VERSION 5.7 ;
BUSBITCHARS "[]" ;
DIVIDERCHAR "/" ;

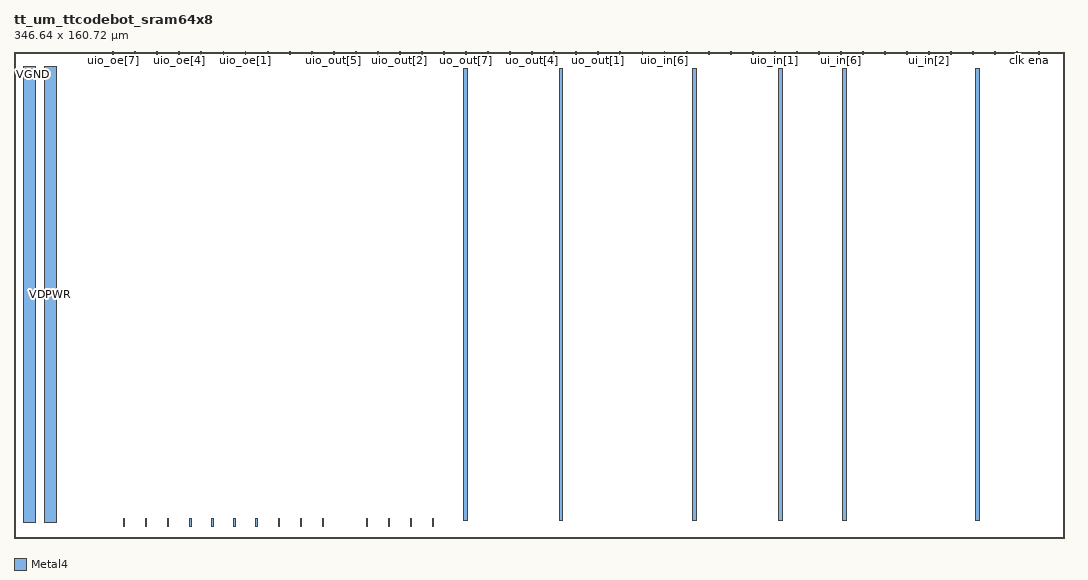
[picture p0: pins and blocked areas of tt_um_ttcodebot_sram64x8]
MACRO tt_um_ttcodebot_sram64x8
  CLASS BLOCK ;
  FOREIGN tt_um_ttcodebot_sram64x8 0 0 ;
  ORIGIN 0 0 ;
  SIZE 346.640 BY 160.720 ;
  PIN clk
    DIRECTION INPUT ;
    USE SIGNAL ;
    PORT
      LAYER Metal4 ;
        RECT 331.090 159.720 331.390 160.720 ;
    END
  END clk
  PIN ena
    DIRECTION INPUT ;
    USE SIGNAL ;
    PORT
      LAYER Metal4 ;
        RECT 338.370 159.720 338.670 160.720 ;
    END
  END ena
  PIN rst_n
    DIRECTION INPUT ;
    USE SIGNAL ;
    PORT
      LAYER Metal4 ;
        RECT 323.810 159.720 324.110 160.720 ;
    END
  END rst_n
  PIN ui_in[0]
    DIRECTION INPUT ;
    USE SIGNAL ;
    PORT
      LAYER Metal4 ;
        RECT 316.530 159.720 316.830 160.720 ;
    END
  END ui_in[0]
  PIN ui_in[1]
    DIRECTION INPUT ;
    USE SIGNAL ;
    PORT
      LAYER Metal4 ;
        RECT 309.250 159.720 309.550 160.720 ;
    END
  END ui_in[1]
  PIN ui_in[2]
    DIRECTION INPUT ;
    USE SIGNAL ;
    PORT
      LAYER Metal4 ;
        RECT 301.970 159.720 302.270 160.720 ;
    END
  END ui_in[2]
  PIN ui_in[3]
    DIRECTION INPUT ;
    USE SIGNAL ;
    PORT
      LAYER Metal4 ;
        RECT 294.690 159.720 294.990 160.720 ;
    END
  END ui_in[3]
  PIN ui_in[4]
    DIRECTION INPUT ;
    USE SIGNAL ;
    PORT
      LAYER Metal4 ;
        RECT 287.410 159.720 287.710 160.720 ;
    END
  END ui_in[4]
  PIN ui_in[5]
    DIRECTION INPUT ;
    USE SIGNAL ;
    PORT
      LAYER Metal4 ;
        RECT 280.130 159.720 280.430 160.720 ;
    END
  END ui_in[5]
  PIN ui_in[6]
    DIRECTION INPUT ;
    USE SIGNAL ;
    PORT
      LAYER Metal4 ;
        RECT 272.850 159.720 273.150 160.720 ;
    END
  END ui_in[6]
  PIN ui_in[7]
    DIRECTION INPUT ;
    USE SIGNAL ;
    PORT
      LAYER Metal4 ;
        RECT 265.570 159.720 265.870 160.720 ;
    END
  END ui_in[7]
  PIN uio_in[0]
    DIRECTION INPUT ;
    USE SIGNAL ;
    PORT
      LAYER Metal4 ;
        RECT 258.290 159.720 258.590 160.720 ;
    END
  END uio_in[0]
  PIN uio_in[1]
    DIRECTION INPUT ;
    USE SIGNAL ;
    PORT
      LAYER Metal4 ;
        RECT 251.010 159.720 251.310 160.720 ;
    END
  END uio_in[1]
  PIN uio_in[2]
    DIRECTION INPUT ;
    USE SIGNAL ;
    PORT
      LAYER Metal4 ;
        RECT 243.730 159.720 244.030 160.720 ;
    END
  END uio_in[2]
  PIN uio_in[3]
    DIRECTION INPUT ;
    USE SIGNAL ;
    PORT
      LAYER Metal4 ;
        RECT 236.450 159.720 236.750 160.720 ;
    END
  END uio_in[3]
  PIN uio_in[4]
    DIRECTION INPUT ;
    USE SIGNAL ;
    PORT
      LAYER Metal4 ;
        RECT 229.170 159.720 229.470 160.720 ;
    END
  END uio_in[4]
  PIN uio_in[5]
    DIRECTION INPUT ;
    USE SIGNAL ;
    PORT
      LAYER Metal4 ;
        RECT 221.890 159.720 222.190 160.720 ;
    END
  END uio_in[5]
  PIN uio_in[6]
    DIRECTION INPUT ;
    USE SIGNAL ;
    PORT
      LAYER Metal4 ;
        RECT 214.610 159.720 214.910 160.720 ;
    END
  END uio_in[6]
  PIN uio_in[7]
    DIRECTION INPUT ;
    USE SIGNAL ;
    PORT
      LAYER Metal4 ;
        RECT 207.330 159.720 207.630 160.720 ;
    END
  END uio_in[7]
  PIN uo_out[0]
    DIRECTION OUTPUT ;
    USE SIGNAL ;
    PORT
      LAYER Metal4 ;
        RECT 200.050 159.720 200.350 160.720 ;
    END
  END uo_out[0]
  PIN uo_out[1]
    DIRECTION OUTPUT ;
    USE SIGNAL ;
    PORT
      LAYER Metal4 ;
        RECT 192.770 159.720 193.070 160.720 ;
    END
  END uo_out[1]
  PIN uo_out[2]
    DIRECTION OUTPUT ;
    USE SIGNAL ;
    PORT
      LAYER Metal4 ;
        RECT 185.490 159.720 185.790 160.720 ;
    END
  END uo_out[2]
  PIN uo_out[3]
    DIRECTION OUTPUT ;
    USE SIGNAL ;
    PORT
      LAYER Metal4 ;
        RECT 178.210 159.720 178.510 160.720 ;
    END
  END uo_out[3]
  PIN uo_out[4]
    DIRECTION OUTPUT ;
    USE SIGNAL ;
    PORT
      LAYER Metal4 ;
        RECT 170.930 159.720 171.230 160.720 ;
    END
  END uo_out[4]
  PIN uo_out[5]
    DIRECTION OUTPUT ;
    USE SIGNAL ;
    PORT
      LAYER Metal4 ;
        RECT 163.650 159.720 163.950 160.720 ;
    END
  END uo_out[5]
  PIN uo_out[6]
    DIRECTION OUTPUT ;
    USE SIGNAL ;
    PORT
      LAYER Metal4 ;
        RECT 156.370 159.720 156.670 160.720 ;
    END
  END uo_out[6]
  PIN uo_out[7]
    DIRECTION OUTPUT ;
    USE SIGNAL ;
    PORT
      LAYER Metal4 ;
        RECT 149.090 159.720 149.390 160.720 ;
    END
  END uo_out[7]
  PIN uio_out[0]
    DIRECTION OUTPUT ;
    USE SIGNAL ;
    PORT
      LAYER Metal4 ;
        RECT 141.810 159.720 142.110 160.720 ;
    END
  END uio_out[0]
  PIN uio_out[1]
    DIRECTION OUTPUT ;
    USE SIGNAL ;
    PORT
      LAYER Metal4 ;
        RECT 134.530 159.720 134.830 160.720 ;
    END
  END uio_out[1]
  PIN uio_out[2]
    DIRECTION OUTPUT ;
    USE SIGNAL ;
    PORT
      LAYER Metal4 ;
        RECT 127.250 159.720 127.550 160.720 ;
    END
  END uio_out[2]
  PIN uio_out[3]
    DIRECTION OUTPUT ;
    USE SIGNAL ;
    PORT
      LAYER Metal4 ;
        RECT 119.970 159.720 120.270 160.720 ;
    END
  END uio_out[3]
  PIN uio_out[4]
    DIRECTION OUTPUT ;
    USE SIGNAL ;
    PORT
      LAYER Metal4 ;
        RECT 112.690 159.720 112.990 160.720 ;
    END
  END uio_out[4]
  PIN uio_out[5]
    DIRECTION OUTPUT ;
    USE SIGNAL ;
    PORT
      LAYER Metal4 ;
        RECT 105.410 159.720 105.710 160.720 ;
    END
  END uio_out[5]
  PIN uio_out[6]
    DIRECTION OUTPUT ;
    USE SIGNAL ;
    PORT
      LAYER Metal4 ;
        RECT 98.130 159.720 98.430 160.720 ;
    END
  END uio_out[6]
  PIN uio_out[7]
    DIRECTION OUTPUT ;
    USE SIGNAL ;
    PORT
      LAYER Metal4 ;
        RECT 90.850 159.720 91.150 160.720 ;
    END
  END uio_out[7]
  PIN uio_oe[0]
    DIRECTION OUTPUT ;
    USE SIGNAL ;
    PORT
      LAYER Metal4 ;
        RECT 83.570 159.720 83.870 160.720 ;
    END
  END uio_oe[0]
  PIN uio_oe[1]
    DIRECTION OUTPUT ;
    USE SIGNAL ;
    PORT
      LAYER Metal4 ;
        RECT 76.290 159.720 76.590 160.720 ;
    END
  END uio_oe[1]
  PIN uio_oe[2]
    DIRECTION OUTPUT ;
    USE SIGNAL ;
    PORT
      LAYER Metal4 ;
        RECT 69.010 159.720 69.310 160.720 ;
    END
  END uio_oe[2]
  PIN uio_oe[3]
    DIRECTION OUTPUT ;
    USE SIGNAL ;
    PORT
      LAYER Metal4 ;
        RECT 61.730 159.720 62.030 160.720 ;
    END
  END uio_oe[3]
  PIN uio_oe[4]
    DIRECTION OUTPUT ;
    USE SIGNAL ;
    PORT
      LAYER Metal4 ;
        RECT 54.450 159.720 54.750 160.720 ;
    END
  END uio_oe[4]
  PIN uio_oe[5]
    DIRECTION OUTPUT ;
    USE SIGNAL ;
    PORT
      LAYER Metal4 ;
        RECT 47.170 159.720 47.470 160.720 ;
    END
  END uio_oe[5]
  PIN uio_oe[6]
    DIRECTION OUTPUT ;
    USE SIGNAL ;
    PORT
      LAYER Metal4 ;
        RECT 39.890 159.720 40.190 160.720 ;
    END
  END uio_oe[6]
  PIN uio_oe[7]
    DIRECTION OUTPUT ;
    USE SIGNAL ;
    PORT
      LAYER Metal4 ;
        RECT 32.610 159.720 32.910 160.720 ;
    END
  END uio_oe[7]
  PIN VGND
    DIRECTION INOUT ;
    USE GROUND ;
    PORT
      LAYER Metal4 ;
        RECT 3.000 5.000 7.000 155.720 ;
      LAYER Metal4 ;
        RECT 36.200 3.700 36.600 6.400 ;
      LAYER Metal4 ;
        RECT 43.480 3.700 43.880 6.400 ;
      LAYER Metal4 ;
        RECT 50.760 3.700 51.160 6.400 ;
      LAYER Metal4 ;
        RECT 58.040 3.700 58.440 6.400 ;
      LAYER Metal4 ;
        RECT 65.320 3.700 65.720 6.400 ;
      LAYER Metal4 ;
        RECT 72.600 3.700 73.000 6.400 ;
      LAYER Metal4 ;
        RECT 79.880 3.700 80.280 6.400 ;
      LAYER Metal4 ;
        RECT 87.160 3.700 87.560 6.400 ;
      LAYER Metal4 ;
        RECT 94.440 3.700 94.840 6.400 ;
      LAYER Metal4 ;
        RECT 101.720 3.700 102.120 6.400 ;
      LAYER Metal4 ;
        RECT 116.280 3.700 116.680 6.400 ;
      LAYER Metal4 ;
        RECT 123.560 3.700 123.960 6.400 ;
      LAYER Metal4 ;
        RECT 130.840 3.700 131.240 6.400 ;
      LAYER Metal4 ;
        RECT 138.120 3.700 138.520 6.400 ;
    END
  END VGND
  PIN VDPWR
    DIRECTION INOUT ;
    USE POWER ;
    PORT
      LAYER Metal4 ;
        RECT 10.000 5.000 14.000 155.720 ;
      LAYER Metal4 ;
        RECT 148.500 5.755 149.700 155.065 ;
      LAYER Metal4 ;
        RECT 180.000 5.755 181.200 155.065 ;
      LAYER Metal4 ;
        RECT 224.000 5.755 225.200 155.065 ;
      LAYER Metal4 ;
        RECT 252.500 5.755 253.700 155.065 ;
      LAYER Metal4 ;
        RECT 273.500 5.755 274.700 155.065 ;
      LAYER Metal4 ;
        RECT 317.500 5.755 318.700 155.065 ;
    END
  END VDPWR
END tt_um_ttcodebot_sram64x8

END LIBRARY
